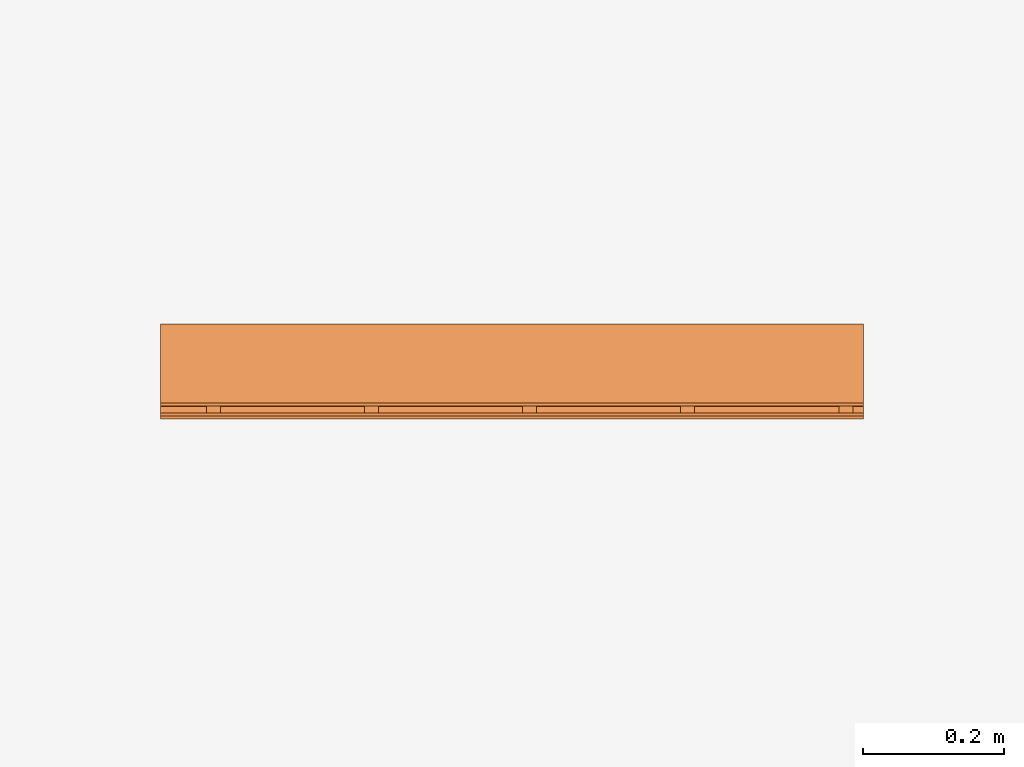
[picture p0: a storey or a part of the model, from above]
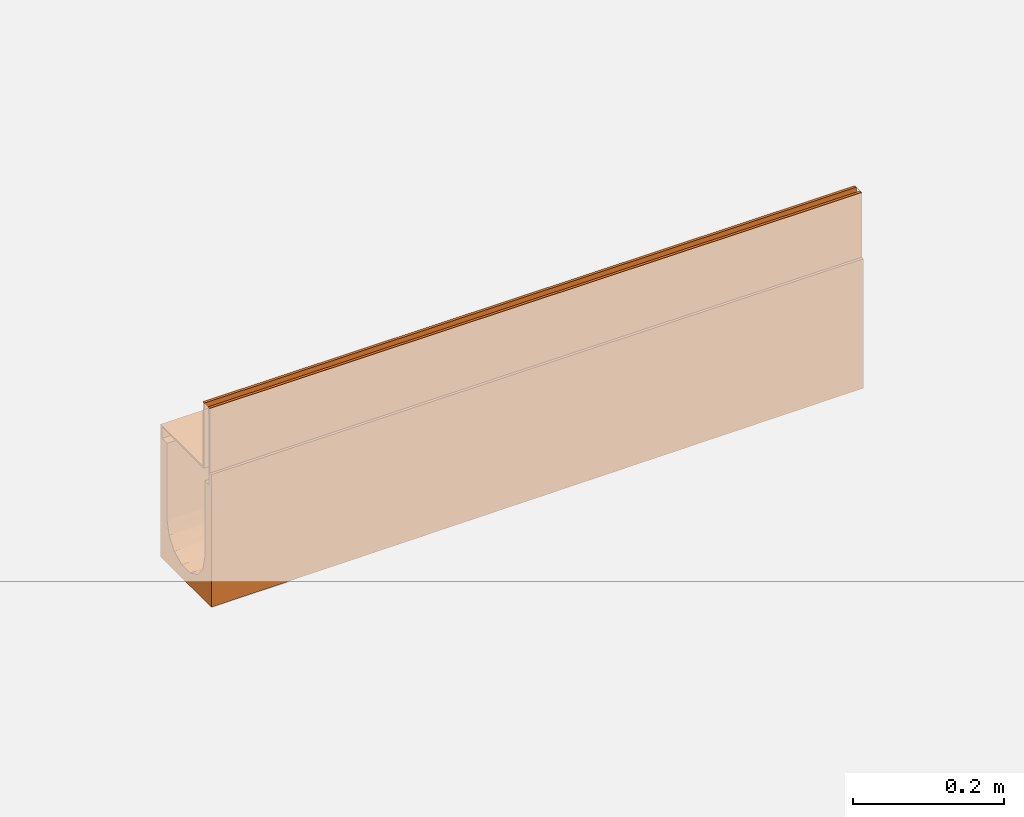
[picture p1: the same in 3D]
Properties of the parts of a building model (IFC2X3)

# File
Description: ViewDefinition [CoordinationView]
File name: 23013 - No 13 Sloping Channel - 1000mm LG - Invert Depth 190-195mm.ifc
Time: 2013-10-31T17:27:08
Written by: Autodesk Revit 2013
Made in: 20120221_2030(x64)

# IfcProject, Project Number
LongName: Project Name; Phase: Project Status

# IfcSite, Default
RefLatitude: 42, 21, 30, 344238; RefLongitude: -71, -3, -35, -194702; RefElevation: 0 mm

# IfcBuilding
Pset_BuildingCommon - NumberOfStoreys: 1
Other - Project Number: Project Number; Project Name: Project Name; Project Issue Date: Issue Date; Project Status: Project Status; Project Address: ## Street City, State Zip; Client Name: Owner

# IfcBuildingStorey, Level 1
LongName: Level 1; Elevation: 0 mm
Constraints - Elevation Base: 0; Elevation: 0 mm
Graphics - Line Weight: 1; Color: 0; Symbol at End 1 Default: no; Symbol at End 2 Default: yes; Line Pattern: Center; Symbol: M_Level Head - Circle: M_Level Head - Circle
Dimensions - Computation Height: 0 mm
Identity Data - Structural: no; Building Story: yes; Name: Level 1

# IfcBuildingElementProxy: 23013 - No 13 Sloping Channel - 1000mm LG - Invert Depth 190/195mm, Civil-Drainage-Channel-ACO-MultiDrain-M100D-Brickslot-Channel-System:23013 - No 13 Sloping Channel - 1000mm LG - Invert Depth 190/195mm:23013 - No 13 Sloping Channel - 1000mm LG - Invert Depth 190/195mm:196059
In: Level 1
Material: Steel, Galvanized, Vienite® Synthetic Resin Concrete
Phasing - Phase Created: New Construction
Dimensions - Brickslot Void Length: 1000 mm; Length: 1000 mm; EndCap Position: 1000 mm; Brickslot Void Depth: 0 mm; Custom_Void_length: 0 mm; Volume: 10776208 mm3; Brickslot Access Unit Void Depth: -6500 mm; FloorCut_Length: -1000 mm; Brickslot Access Unit Void Bottom Depth: -6605 mm; SlopingOverallDepth: 210 mm; SlopingInvertDepth: 140 mm; Floor Cut Gap: 105 mm; SlopingEndOverallDepth: 215 mm; EndCap_Height: 215 mm; FloorCut_Width: 135 mm; InvDepth: 80 mm; Access_Custom_Void_Length: 0 mm; GratingLength: -1000 mm; Length Drain: -1000 mm; Depth: 150 mm; SlopingEndInvertDepth: 145 mm; Brickslot Access Unit Floor Cut Length: 500 mm; ShallowInvDepth: 55 mm; ShallowOverallDepth: 75 mm; FloorCut_Depth: 215 mm
Construction - 23404_Universal Endcap (Male End): no; 23461_Load Class C250_Brickslot Grating_Galvanized Steel_500mm Long: no; 23462_Load Class C250_Brickslot Access Unit_Galvanised Steel_500mm Long: no; 23467_Load Class D400_Brickslot Access Unit_Galvanised Steel_500mm Long: no; 23404_Universal Endcap (Female End): no; 23465_Load Class D400_Brickslot Grating_Galvanized Steel_1000mm Long: yes; 23460_Load Class C250_Brickslot Grating_Galvanized Steel_1000mm Long: no; 23466_Load Class D400_Brickslot Grating_Galvanized Steel_500mm Long: no; Constant Depth Junction Channel: no; Shallow Depth Channel with seal: no; Shallow Depth Channel: no; Sloping Channel: yes; 23410_Sump Unit: no; Constant Depth Channel: no
Constraints - Moves With Nearby Elements: no; Level: Level: Level 1
Pset_BuildingElementProxyCommon - Reference: 23013 - No 13 Sloping Channel - 1000mm LG - Invert Depth 190/195mm
Identity Data - OmniClass Title: Rainwater Removal; Watermark 1: This file is the property of ACO Technologies PLC; Installation guidelines: http://www.aco.co.uk/download.php?id=173; URL: www.aco.co.uk; Watermarked With: BIM Manager Premium Suite; Cost: 0; Model: ACO MultiDrain MD Brickslot- M100D; Price: POA - contact ACO; OmniClass Number: 23.70.50.24; Assembly Description: Rain Water Drainage; Assembly Code: D2040; e-mail Technical: technical@aco.co.uk; Manufacturer: ACO Technologies plc - ACO Water Management Division; Telephone: +44 (0)1462 816666; Address: ACO Business Park, Hitchin Road, Shefford, Bedfordshire, United Kingdom SG17 5TE; Model Description: Channel drainage system; Watermark 2: This file is water marked and users are prohibited to reproduce, adapt, distribute this information; Product Code: 23013; Fax: +44 (0)1462 815895; Maintenance guidelines: http://www.aco.co.uk/download.php?id=173; Type Comments: ACO MultiDrain M100D No 13 Sloping Channel 1000mm Long; e-mail Sales: customersupport@aco.co.uk; Product brochure: http://www.aco.co.uk/download.php?id=173; Product Page URL: http://www.aco.co.uk/product_detail.php?id=58
Data - Concrete Surround Volume - Load Class D 400 - Concrete Pavement: N/A; Load Class: A 15 - D 400; Concrete Surround Volume - Load Class B 125 - C 250 - Concrete Pavement: N/A; Pre-formed Outlet Ø: N/A; Product Standard: BS EN 1433:2002, CE marked; ACO Hydraulic Design Software: http://www.acodesign.co.uk; Invert Depth: 190mm/195mm; Channel C.S.A: N/A; Installation - Concrete Grade: Refer to brochure; Product Weight: 17.1 Kg; Product Dimensions: 1000mm x 135mm x 210mm/215mm (LxWxH); Concrete Surround Volume - Load Class A 15 - Concrete Pavement: N/A; Hydraulic Performance: http://www.aco.co.uk/download.php?id=173
Model Properties - Brickslot Access Unit Product code 23462: Load Class C250 - Brickslot Access Unit Galvanised Steel - 500mm long x 105mm high - 10mm Slot - Intake area - 10000mm²/m - 6.4 Kg; Brickslot Grating Product code 23465: Load Class D400 - Brickslot Galvanised Steel - 1000mm long x 105mm high - 10mm Slot - Intake area - 10000mm²/m - 6.6 Kg; Brickslot Grating Product code 23461: Load Class C250 - Brickslot Galvanised Steel - 500mm long x 105mm high - 10mm Slot - Intake area - 10000mm²/m -3.3 Kg; End Cap Product code 23404: No 306 Universal End Cap - 135mm wide x 300mm long - Spigot Ø110mm x 50mm long - Silver - Polypropylene - 0.16kg; Brickslot Grating Product code 23466: Load Class D400 - Brickslot Galvanised Steel - 500mm long x 105mm high - 10mm Slot - Intake area - 10000mm²/m - 3.3 Kg; Brickslot Grating Product code 23460: Load Class C250 - Brickslot Galvanised Steel - 1000mm long x 105mm high - 10mm Slot - Intake area - 10000mm²/m - 6.6 Kg; Brickslot Access Unit Product code 23467: Load Class D400 - Brickslot Access Unit Galvanised Steel - 500mm long x 105mm high - 10mm Slot - Intake area - 10000mm²/m - 6.4 Kg
General - TagNumber: 0; SerialNumber: 0
Other - Created By: www.aco.co.uk; Revision: 1; Watermarked By: www.aco.co.uk
Materials and Finishes - Edge Rail Finish: Pre-galvanised; Edge Rail Colour: Silver; Channel Material: Vienite® Synthetic Resin Concrete; Channel Colour: Brown; Edge Rail Material: Steel
Green Building Properties - Channel Recyclable: Fully recyclable; Edge Rail Recyclable: Fully recyclable; Edge Rail Recycled Material Content: Between 40% - 90%; Channel Recycled Material Content: 20% minimum

# IfcOpeningElement: Recess (2)
In: Level 1
Dimensions - Perimeter: 20000 mm; Volume: 24969085000 mm3; Area: 25000000 mm2; Thickness: 1000 mm
Phasing - Phase Created: New Construction
Constraints - Room Bounding: yes; Level: Level: Level 1; Height Offset From Level: 0 mm; Related to Mass: no
Structural - Structural: no; Enable Analytical Model: no
Analytical Properties - Heat Transfer Coefficient (U): 0.837; Absorptance: 0.1; Thermal Resistance (R): 1.19474; Thermal mass: 1359800; Roughness: 1
Construction - Function: 0; Default Thickness: 1000 mm
Graphics - Coarse Scale Fill Color: 0
Materials and Finishes - Structural Material: Earth

# IfcSlab: Floor:Generic Floor - 1000mm, Floor:Generic Floor - 1000mm:193825
In: Level 1
PredefinedType: FLOOR; Material: Earth 1000 mm
Dimensions - Perimeter: 20000 mm; Volume: 24969085000 mm3; Area: 25000000 mm2; Thickness: 1000 mm
Phasing - Phase Created: New Construction
Constraints - Room Bounding: yes; Level: Level: Level 1; Height Offset From Level: 0 mm; Related to Mass: no
Structural - Structural: no; Enable Analytical Model: no
Pset_SlabCommon - Reference: Generic Floor - 1000mm; IsExternal: no; LoadBearing: yes
Analytical Properties - Heat Transfer Coefficient (U): 0.837; Absorptance: 0.1; Thermal Resistance (R): 1.19474; Thermal mass: 1359800; Roughness: 1
Construction - Function: 0; Default Thickness: 1000 mm
Graphics - Coarse Scale Fill Color: 0
Materials and Finishes - Structural Material: Earth
